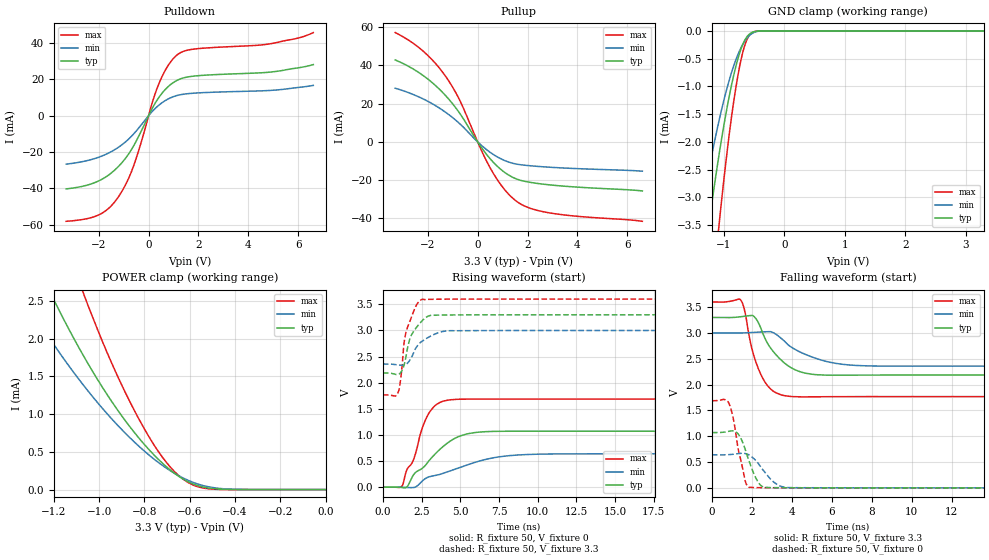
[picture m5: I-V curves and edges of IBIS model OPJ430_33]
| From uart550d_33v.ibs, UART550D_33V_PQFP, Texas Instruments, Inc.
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[Model]   OPJ430_33
Model_type  3-state
Enable   Active-Low
Vref =   1.65
Rref =   50
Cref =   15p
Vmeas =   1.65
| variable   typ   min   max
C_comp   0.50pF   0.44pF   0.54pF
| C_pullup   1.66pF   0.41pF   2.42pF
| C_pulldown   1.43pF   0.59pF   2.28pF
| C_tri-state   0.50pF   0.44pF   0.54pF
[Temperature Range]   40   125   -40
| Ambient temperature   25   110   -40
[Voltage range]   3.3   3   3.6
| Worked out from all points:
|   slope of the pulldown table from 0 to 0.495 V, typ, clamps not added: 42.5 ohm
|   slope of the pullup table from 0 to 0.495 V, typ, clamps not added: 56.6 ohm
|   GND clamp passes 1 mA (typ) near -0.88 V on its own axis
|   POWER clamp passes 1 mA (typ) near -0.91 V on its own axis
|   rising waveform, R_fixture 50, V_fixture 0: 20-80 % time 2.3ns typ, 3.79ns min, 1.29ns max; typ from 0 V to 1.07 V
|   falling waveform, R_fixture 50, V_fixture 3.3: 20-80 % time 1.2ns typ, 1.84ns min, 792ps max; typ from 3.3 V to 2.19 V
|   rising waveform, R_fixture 50, V_fixture 3.3: 20-80 % time 789ps typ, 1.11ns min, 641ps max; typ from 2.19 V to 3.3 V
|   falling waveform, R_fixture 50, V_fixture 0: 20-80 % time 608ps typ, 815ps min, 493ps max; typ from 1.07 V to 0 V
[GND Clamp]
| OPJ430_33
|   Voltage   I(typ)   I(min)   I(max)
-3.3V     -27.18mA   -19.9mA    -37.91mA
-1.425V   -4.992mA   -3.561mA   -7.606mA
-1.39V    -4.679mA   -3.339mA   -7.148mA
-1.26V    -3.575mA   -2.559mA   -5.517mA
-1.23V    -3.334mA   -2.389mA   -5.157mA
-1.08V    -2.218mA   -1.608mA   -3.473mA
-920mV    -1.216mA   -914.9uA   -1.925mA
-785mV    -563.9uA   -469.6uA   -902.2uA
-720mV    -332.2uA   -308.6uA   -530.4uA
-655mV    -167uA     -184.1uA   -258.3uA
-540mV    -30.63uA   -50.53uA   -36.97uA
3.3V      95.1pA     389.9nA    69.14pA
[POWER Clamp]
| OPJ430_33
|   Voltage   I(typ)   I(min)   I(max)
-3.3V     25.12mA    18.19mA    35.05mA
-1.35V    3.491mA    2.624mA    5.202mA
-1.33V    3.353mA    2.525mA    4.995mA
-1.2V     2.515mA    1.921mA    3.728mA
-1.07V    1.777mA    1.386mA    2.606mA
-1.05V    1.673mA    1.31mA     2.448mA
-945mV    1.17mA     939uA      1.679mA
-825mV    685.1uA    576.1uA    938uA
-715mV    334.5uA    308.7uA    406.2uA
-630mV    140.7uA    154.7uA    139.2uA
-510mV    17.49uA    32.71uA    8.284uA
-47.99fV  95.1pA     355.2pA    79.7pA
[Pulldown]
| OPJ430_33
|   Voltage   I(typ)   I(min)   I(max)
-3.3V     -40.27mA   -26.63mA   -58.11mA
-1.985V   -35.79mA   -22.77mA   -54.53mA
-1.565V   -32.27mA   -20.25mA   -50.55mA
-1.19V    -27.67mA   -17.18mA   -44.28mA
-600mV    -16.61mA   -10.03mA   -27.64mA
160mV     4.407mA    2.542mA    7.775mA
425mV     10.33mA    5.975mA    18.02mA
785mV     16.05mA    9.264mA    27.72mA
1.16V     19.65mA    11.24mA    33.7mA
1.865V    21.94mA    12.51mA    36.83mA
4.86V     24.05mA    13.96mA    39.63mA
6.6V      28.21mA    16.74mA    45.85mA
[Pullup]
| OPJ430_33
|   Voltage   I(typ)   I(min)   I(max)
-3.3V     42.76mA    27.98mA    57.05mA
-2.215V   34.92mA    22.6mA     47.73mA
-1.745V   30.06mA    19.33mA    41.77mA
-1.32V    24.65mA    15.76mA    34.9mA
-715mV    14.86mA    9.436mA    21.67mA
125mV     -2.443mA   -1.519mA   -3.711mA
545mV     -9.491mA   -5.878mA   -14.58mA
1.035V    -15.51mA   -9.506mA   -24.23mA
1.535V    -19.29mA   -11.58mA   -30.82mA
2.085V    -21.14mA   -12.49mA   -34.63mA
2.95V     -22.59mA   -13.33mA   -37.29mA
6.6V      -25.67mA   -15.35mA   -41.53mA
[Ramp]
| OPJ430_33
| variable   typ   min   max
dV/dt_r   0.65/2.33E-09   0.39/3.81E-09   1.02/1.31E-09
dV/dt_f   0.69/1.23E-09   0.40/1.89E-09   1.14/8.14E-10
R_load = 50
[Rising Waveform]
| OPJ430_33
R_fixture =   50
C_fixture =   0
L_fixture =   0
V_fixture =   0
V_fixture_min = 0
V_fixture_max = 0
|   Time   V(typ)   V(min)   V(max)
0s        -5.9uV     -10.96uV   -1.555uV
1.25ns    -5.951mV   18.57uV    23.79mV
1.545ns   3.446mV    -3.772mV   329.4mV
2.01ns    249.4mV    -3.678mV   551.1mV
2.465ns   346.1mV    93.4mV     1.058V
2.84ns    452.5mV    182mV      1.344V
3.95ns    794.3mV    272.3mV    1.652V
5.555ns   1.028V     436.9mV    1.686V
8.78ns    1.072V     618.1mV    1.687V
24.99ns   1.072V     640.1mV    1.687V
[Falling Waveform]
| OPJ430_33
R_fixture =   50
C_fixture =   0
L_fixture =   0
V_fixture =   3.3
V_fixture_min = 3
V_fixture_max = 3.6
|   Time   V(typ)   V(min)   V(max)
0s        3.3V       3V         3.6V
1.45ns    3.315V     2.999V     3.633V
1.645ns   3.324V     3.002V     3.422V
2.04ns    3.339V     3.01V      2.639V
2.42ns    3.118V     3.018V     2.221V
2.94ns    2.706V     3.024V     1.915V
3.595ns   2.429V     2.853V     1.788V
4.715ns   2.219V     2.579V     1.762V
7.185ns   2.183V     2.372V     1.767V
24.99ns   2.185V     2.357V     1.767V
[Rising Waveform]
| OPJ430_33
R_fixture =   50
C_fixture =   0
L_fixture =   0
V_fixture =   3.3
V_fixture_min = 3
V_fixture_max = 3.6
|   Time   V(typ)   V(min)   V(max)
0s        2.185V     2.357V     1.767V
815ps     2.161V     2.347V     1.744V
1.015ns   2.162V     2.338V     1.837V
1.155ns   2.196V     2.335V     2.081V
1.36ns    2.326V     2.337V     2.737V
1.485ns   2.488V     2.352V     2.954V
1.815ns   2.896V     2.468V     3.232V
2.535ns   3.185V     2.794V     3.595V
4.34ns    3.297V     2.996V     3.6V
24.99ns   3.3V       3V         3.6V
[Falling Waveform]
| OPJ430_33
R_fixture =   50
C_fixture =   0
L_fixture =   0
V_fixture =   0
V_fixture_min = 0
V_fixture_max = 0
|   Time   V(typ)   V(min)   V(max)
0s        1.071V     639.9mV    1.687V
860ps     1.097V     643.5mV    1.627V
1.07ns    1.103V     650.7mV    1.34V
1.365ns   1.016V     665.3mV    656.6mV
1.67ns    740.1mV    663.9mV    128mV
1.87ns    508.1mV    633.8mV    9.126mV
2.495ns   32.43mV    375.6mV    3.404mV
3.16ns    3.906mV    93.47mV    729uV
3.805ns   2.212mV    5.655mV    24.1uV
24.99ns   258.8nV    181.6nV    85.52nV
